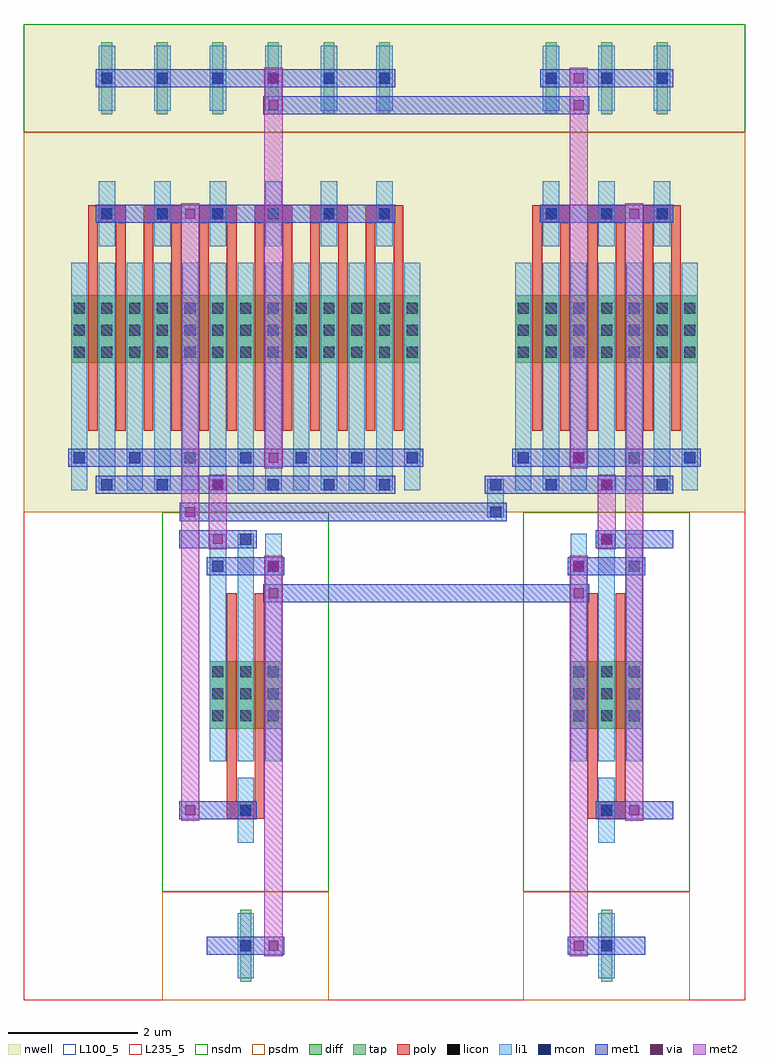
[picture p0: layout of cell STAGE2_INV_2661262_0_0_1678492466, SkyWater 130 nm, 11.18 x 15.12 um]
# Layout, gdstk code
from math import pi, radians
import gdstk
lib = gdstk.Library(unit=1e-6, precision=1e-09)
def R(c, l, rs):  # rectangles x0, y0, x1, y1
    for r in rs: c.add(gdstk.rectangle(r[:2], r[2:], *l))
def A(c, l, x, y, w, h, nx, ny, dx, dy):  # array of equal rectangles
    R(c, l, [(x+i*dx, y+j*dy, x+i*dx+w, y+j*dy+h) for i in range(nx) for j in range(ny)])
def P(c, l, *ps):  # polygons
    for p in ps: c.add(gdstk.Polygon(p, *l))
nwell = (64, 20)
diff = (65, 20)
tap = (65, 44)
poly = (66, 20)
licon = (66, 44)
li1 = (67, 20)
mcon = (67, 44)
met1 = (68, 20)
via = (68, 44)
met2 = (69, 20)
nsdm = (93, 44)
psdm = (94, 20)
L100_5 = (100, 5)
L235_5 = (235, 5)

nmos_s_54487678_x1_y1_16 = lib.new_cell('NMOS_S_54487678_X1_Y1_1678492463_1678492466')
R(nmos_s_54487678_x1_y1_16, diff, [(0.735,2.31,1.845,3.36)])
R(nmos_s_54487678_x1_y1_16, tap, [(1.205,6.16,1.375,7.28)])
R(nmos_s_54487678_x1_y1_16, poly, [(1,1.26,1.15,4.62), (1.43,1.26,1.58,4.62), (1,4.485,1.58,4.755)])
A(nmos_s_54487678_x1_y1_16, licon, 0.775, 2.39, 0.17, 0.17, 3, 3, 0.43, 0.34)
R(nmos_s_54487678_x1_y1_16, licon, [(1.205,4.535,1.375,4.705), (1.205,6.635,1.375,6.805)])
A(nmos_s_54487678_x1_y1_16, li1, 0.735, 0.335, 0.25, 3.53, 3, 1, 0.43, 0)
R(nmos_s_54487678_x1_y1_16, li1, [(1.165,4.115,1.415,5.125), (1.165,6.215,1.415,7.225)])
R(nmos_s_54487678_x1_y1_16, mcon, [(1.205,0.335,1.375,0.505), (0.775,0.755,0.945,0.925), (1.635,0.755,1.805,0.925), (1.205,4.535,1.375,4.705), (1.205,6.635,1.375,6.805)])
R(nmos_s_54487678_x1_y1_16, met1, [(0.26,0.28,1.46,0.56), (0.69,0.7,1.89,0.98), (0.26,4.48,1.46,4.76), (0.69,6.58,1.89,6.86)])
R(nmos_s_54487678_x1_y1_16, via, [(1.645,0.765,1.795,0.915), (1.645,6.645,1.795,6.795)])
R(nmos_s_54487678_x1_y1_16, met2, [(1.58,0.68,1.86,6.88)])
R(nmos_s_54487678_x1_y1_16, nsdm, [(0,0,2.58,5.88)])
R(nmos_s_54487678_x1_y1_16, psdm, [(0,5.88,2.58,7.56)])
R(nmos_s_54487678_x1_y1_16, L100_5, [(0,0,2.58,7.56)])

pmos_s_55262173_x3_y1_16 = lib.new_cell('PMOS_S_55262173_X3_Y1_1678492464_1678492466')
R(pmos_s_55262173_x3_y1_16, nwell, [(0,0,4.3,7.56)])
R(pmos_s_55262173_x3_y1_16, diff, [(0.735,2.31,3.565,3.36)])
A(pmos_s_55262173_x3_y1_16, tap, 1.205, 6.16, 0.17, 1.12, 3, 1, 0.86, 0)
A(pmos_s_55262173_x3_y1_16, poly, 1, 1.26, 0.15, 3.36, 6, 1, 0.43, 0)
A(pmos_s_55262173_x3_y1_16, poly, 1, 4.485, 0.58, 0.27, 3, 1, 0.86, 0)
A(pmos_s_55262173_x3_y1_16, licon, 0.775, 2.39, 0.17, 0.17, 3, 3, 0.43, 0.34)
A(pmos_s_55262173_x3_y1_16, licon, 1.635, 2.39, 0.17, 0.17, 3, 3, 0.43, 0.34)
A(pmos_s_55262173_x3_y1_16, licon, 2.495, 2.39, 0.17, 0.17, 3, 3, 0.43, 0.34)
A(pmos_s_55262173_x3_y1_16, licon, 1.205, 4.535, 0.17, 0.17, 3, 2, 0.86, 2.1)
A(pmos_s_55262173_x3_y1_16, li1, 0.735, 0.335, 0.25, 3.53, 7, 1, 0.43, 0)
A(pmos_s_55262173_x3_y1_16, li1, 1.165, 4.115, 0.25, 1.01, 3, 2, 0.86, 2.1)
A(pmos_s_55262173_x3_y1_16, mcon, 1.205, 0.335, 0.17, 0.17, 3, 2, 0.86, 4.2)
A(pmos_s_55262173_x3_y1_16, mcon, 0.775, 0.755, 0.17, 0.17, 4, 1, 0.86, 0)
A(pmos_s_55262173_x3_y1_16, mcon, 1.205, 6.635, 0.17, 0.17, 3, 1, 0.86, 0)
R(pmos_s_55262173_x3_y1_16, met1, [(1.12,0.28,3.18,0.56), (0.69,0.7,3.61,0.98), (1.12,4.48,3.18,4.76), (1.12,6.58,3.18,6.86)])
R(pmos_s_55262173_x3_y1_16, via, [(2.505,0.765,2.655,0.915), (2.505,6.645,2.655,6.795)])
R(pmos_s_55262173_x3_y1_16, met2, [(2.44,0.68,2.72,6.88)])
R(pmos_s_55262173_x3_y1_16, nsdm, [(0,5.88,4.3,7.56)])
R(pmos_s_55262173_x3_y1_16, psdm, [(0,0,4.3,5.88)])
R(pmos_s_55262173_x3_y1_16, L100_5, [(0,0,4.3,7.56)])

pmos_s_81354572_x6_y1_16 = lib.new_cell('PMOS_S_81354572_X6_Y1_1678492465_1678492466')
R(pmos_s_81354572_x6_y1_16, nwell, [(0,0,6.88,7.56)])
R(pmos_s_81354572_x6_y1_16, diff, [(0.735,2.31,6.145,3.36)])
A(pmos_s_81354572_x6_y1_16, tap, 1.205, 6.16, 0.17, 1.12, 6, 1, 0.86, 0)
A(pmos_s_81354572_x6_y1_16, poly, 1, 1.26, 0.15, 3.36, 12, 1, 0.43, 0)
A(pmos_s_81354572_x6_y1_16, poly, 1, 4.485, 0.58, 0.27, 6, 1, 0.86, 0)
A(pmos_s_81354572_x6_y1_16, licon, 0.775, 2.39, 0.17, 0.17, 3, 3, 0.43, 0.34)
A(pmos_s_81354572_x6_y1_16, licon, 1.635, 2.39, 0.17, 0.17, 3, 3, 0.43, 0.34)
A(pmos_s_81354572_x6_y1_16, licon, 2.495, 2.39, 0.17, 0.17, 3, 3, 0.43, 0.34)
A(pmos_s_81354572_x6_y1_16, licon, 3.355, 2.39, 0.17, 0.17, 3, 3, 0.43, 0.34)
A(pmos_s_81354572_x6_y1_16, licon, 4.215, 2.39, 0.17, 0.17, 3, 3, 0.43, 0.34)
A(pmos_s_81354572_x6_y1_16, licon, 5.075, 2.39, 0.17, 0.17, 3, 3, 0.43, 0.34)
A(pmos_s_81354572_x6_y1_16, licon, 1.205, 4.535, 0.17, 0.17, 6, 2, 0.86, 2.1)
A(pmos_s_81354572_x6_y1_16, li1, 0.735, 0.335, 0.25, 3.53, 13, 1, 0.43, 0)
A(pmos_s_81354572_x6_y1_16, li1, 1.165, 4.115, 0.25, 1.01, 6, 2, 0.86, 2.1)
A(pmos_s_81354572_x6_y1_16, mcon, 1.205, 0.335, 0.17, 0.17, 6, 2, 0.86, 4.2)
A(pmos_s_81354572_x6_y1_16, mcon, 0.775, 0.755, 0.17, 0.17, 7, 1, 0.86, 0)
A(pmos_s_81354572_x6_y1_16, mcon, 1.205, 6.635, 0.17, 0.17, 6, 1, 0.86, 0)
R(pmos_s_81354572_x6_y1_16, met1, [(1.12,0.28,5.76,0.56), (0.69,0.7,6.19,0.98), (1.12,4.48,5.76,4.76), (1.12,6.58,5.76,6.86)])
R(pmos_s_81354572_x6_y1_16, via, [(3.795,0.765,3.945,0.915), (3.795,6.645,3.945,6.795)])
R(pmos_s_81354572_x6_y1_16, met2, [(3.73,0.68,4.01,6.88)])
R(pmos_s_81354572_x6_y1_16, nsdm, [(0,5.88,6.88,7.56)])
R(pmos_s_81354572_x6_y1_16, psdm, [(0,0,6.88,5.88)])
R(pmos_s_81354572_x6_y1_16, L100_5, [(0,0,6.88,7.56)])

stage2_inv_2661262_0_0_1 = lib.new_cell('STAGE2_INV_2661262_0_0_1678492466')
R(stage2_inv_2661262_0_0_1, li1, [(7.185,7.475,7.435,7.645), (7.185,7.475,7.435,7.645), (7.185,7.475,7.435,7.645), (7.185,7.475,7.435,7.645), (7.185,7.56,7.435,7.98), (7.185,7.895,7.435,8.065), (7.185,7.895,7.435,8.065), (7.185,7.895,7.435,8.065), (7.185,7.895,7.435,8.065)])
R(stage2_inv_2661262_0_0_1, mcon, [(7.225,7.475,7.395,7.645), (7.225,7.475,7.395,7.645), (7.225,7.475,7.395,7.645), (7.225,7.475,7.395,7.645), (7.225,7.895,7.395,8.065), (7.225,7.895,7.395,8.065), (7.225,7.895,7.395,8.065), (7.225,7.895,7.395,8.065)])
R(stage2_inv_2661262_0_0_1, met1, [(2.42,2.8,2.74,3.08), (2.42,2.8,2.74,3.08), (2.42,2.8,2.74,3.08), (2.42,2.8,2.74,3.08), (2.42,2.8,2.74,3.08), (2.42,2.8,2.74,3.08), (9.3,2.8,9.62,3.08), (9.3,2.8,9.62,3.08), (3.71,6.16,4.03,6.44), (3.71,6.16,4.03,6.44), (3.87,6.16,8.6,6.44), (8.44,6.16,8.76,6.44), (8.44,6.16,8.76,6.44), (2.85,7,3.17,7.28), (2.85,7,3.17,7.28), (8.87,7,9.19,7.28), (8.87,7,9.19,7.28), (2.42,7.42,2.74,7.7), (2.42,7.42,2.74,7.7), (2.42,7.42,2.74,7.7), (2.42,7.42,2.74,7.7), (2.58,7.42,7.31,7.7), (7.14,7.42,7.48,7.7), (7.14,7.42,7.48,7.7), (7.14,7.42,7.48,7.7), (7.14,7.42,7.48,7.7), (2.85,7.84,3.17,8.12), (2.85,7.84,3.17,8.12), (7.14,7.84,7.48,8.12), (7.14,7.84,7.48,8.12), (7.14,7.84,7.48,8.12), (7.14,7.84,7.48,8.12), (7.31,7.84,8.17,8.12), (8.87,7.84,9.19,8.12), (8.87,7.84,9.19,8.12), (2.42,12.04,2.74,12.32), (2.42,12.04,2.74,12.32), (2.42,12.04,2.74,12.32), (2.42,12.04,2.74,12.32), (2.42,12.04,2.74,12.32), (2.42,12.04,2.74,12.32), (9.3,12.04,9.62,12.32), (9.3,12.04,9.62,12.32), (3.71,13.72,4.03,14), (3.71,13.72,4.03,14), (3.87,13.72,8.6,14), (8.44,13.72,8.76,14), (8.44,13.72,8.76,14)])
P(stage2_inv_2661262_0_0_1, met1, [(0,0),(0,0),(0,0),(0,0)],
  [(0,0),(0,0),(0,0),(0,0)],
  [(0,0),(0,0),(0,0),(0,0)],
  [(0,0),(0,0),(0,0),(0,0)],
  [(0,0),(0,0),(0,0),(0,0)],
  [(0,0),(0,0),(0,0),(0,0)],
  [(0,0),(0,0),(0,0),(0,0)],
  [(0,0),(0,0),(0,0),(0,0)])
R(stage2_inv_2661262_0_0_1, via, [(2.505,2.865,2.655,3.015), (2.505,2.865,2.655,3.015), (2.505,2.865,2.655,3.015), (2.505,2.865,2.655,3.015), (2.505,2.865,2.655,3.015), (2.505,2.865,2.655,3.015), (9.385,2.865,9.535,3.015), (9.385,2.865,9.535,3.015), (3.795,6.225,3.945,6.375), (3.795,6.225,3.945,6.375), (8.525,6.225,8.675,6.375), (8.525,6.225,8.675,6.375), (2.935,7.065,3.085,7.215), (2.935,7.065,3.085,7.215), (8.955,7.065,9.105,7.215), (8.955,7.065,9.105,7.215), (2.505,7.485,2.655,7.635), (2.505,7.485,2.655,7.635), (2.505,7.485,2.655,7.635), (2.505,7.485,2.655,7.635), (2.935,7.905,3.085,8.055), (2.935,7.905,3.085,8.055), (8.955,7.905,9.105,8.055), (8.955,7.905,9.105,8.055), (2.505,12.105,2.655,12.255), (2.505,12.105,2.655,12.255), (2.505,12.105,2.655,12.255), (2.505,12.105,2.655,12.255), (2.505,12.105,2.655,12.255), (2.505,12.105,2.655,12.255), (9.385,12.105,9.535,12.255), (9.385,12.105,9.535,12.255), (3.795,13.785,3.945,13.935), (3.795,13.785,3.945,13.935), (8.525,13.785,8.675,13.935), (8.525,13.785,8.675,13.935)])
R(stage2_inv_2661262_0_0_1, met2, [(2.44,2.78,2.72,3.1), (2.44,2.78,2.72,3.1), (2.44,2.78,2.72,3.1), (2.44,2.78,2.72,3.1), (2.44,2.78,2.72,3.1), (2.44,2.78,2.72,3.1), (9.32,2.78,9.6,3.1), (9.32,2.78,9.6,3.1), (2.44,2.94,2.72,12.18), (9.32,2.94,9.6,12.18), (3.73,6.14,4.01,6.46), (3.73,6.14,4.01,6.46), (8.46,6.14,8.74,6.46), (8.46,6.14,8.74,6.46), (2.87,6.98,3.15,7.3), (2.87,6.98,3.15,7.3), (8.89,6.98,9.17,7.3), (8.89,6.98,9.17,7.3), (2.87,7.14,3.15,7.98), (8.89,7.14,9.17,7.98), (2.44,7.4,2.72,7.72), (2.44,7.4,2.72,7.72), (2.44,7.4,2.72,7.72), (2.44,7.4,2.72,7.72), (2.87,7.82,3.15,8.14), (2.87,7.82,3.15,8.14), (8.89,7.82,9.17,8.14), (8.89,7.82,9.17,8.14), (2.44,12.02,2.72,12.34), (2.44,12.02,2.72,12.34), (2.44,12.02,2.72,12.34), (2.44,12.02,2.72,12.34), (2.44,12.02,2.72,12.34), (2.44,12.02,2.72,12.34), (9.32,12.02,9.6,12.34), (9.32,12.02,9.6,12.34), (3.73,13.7,4.01,14.02), (3.73,13.7,4.01,14.02), (8.46,13.7,8.74,14.02), (8.46,13.7,8.74,14.02)])
P(stage2_inv_2661262_0_0_1, met2, [(0,0),(0,0),(0,0),(0,0)],
  [(0,0),(0,0),(0,0),(0,0)],
  [(0,0),(0,0),(0,0),(0,0)],
  [(0,0),(0,0),(0,0),(0,0)])
R(stage2_inv_2661262_0_0_1, L235_5, [(0,0,11.18,15.12)])
stage2_inv_2661262_0_0_1.add(gdstk.Reference(nmos_s_54487678_x1_y1_16, (10.32,7.56), rotation=pi))
stage2_inv_2661262_0_0_1.add(gdstk.Reference(nmos_s_54487678_x1_y1_16, (2.15,7.56), x_reflection=True))
stage2_inv_2661262_0_0_1.add(gdstk.Reference(pmos_s_55262173_x3_y1_16, (11.18,7.56), rotation=pi, x_reflection=True))
stage2_inv_2661262_0_0_1.add(gdstk.Reference(pmos_s_81354572_x6_y1_16, (0,7.56)))

lib.write_gds('STAGE2_INV_2661262_0_0_1678492466.gds')
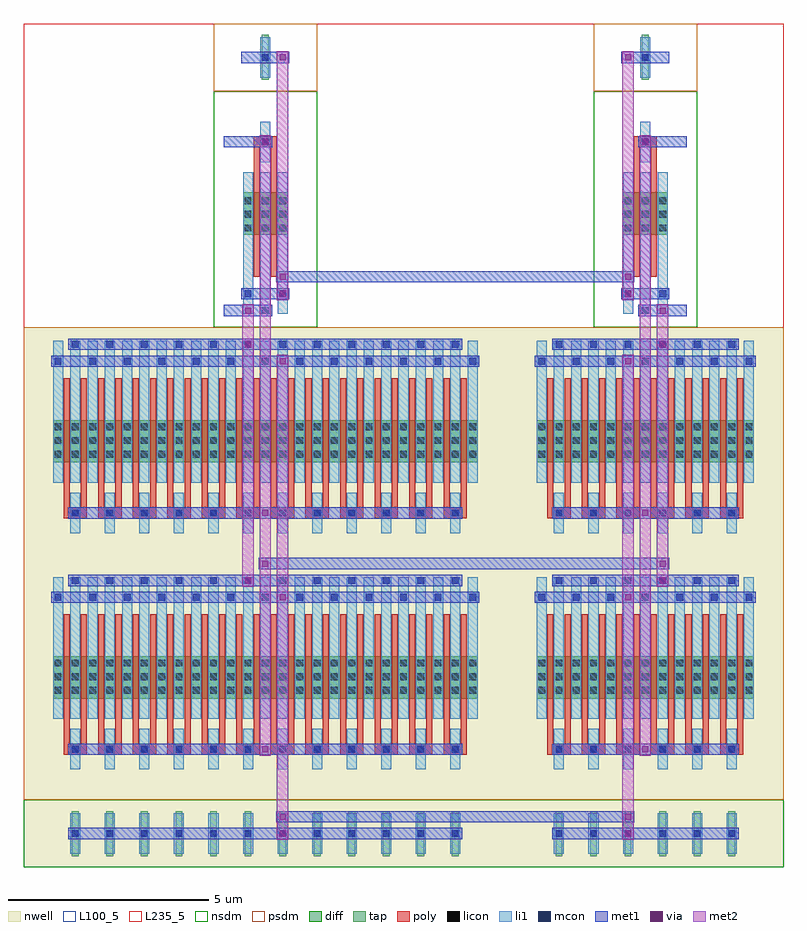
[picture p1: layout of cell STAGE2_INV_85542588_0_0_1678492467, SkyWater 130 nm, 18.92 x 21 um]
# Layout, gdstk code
from math import pi, radians
import gdstk
lib = gdstk.Library(unit=1e-6, precision=1e-09)
def R(c, l, rs):  # rectangles x0, y0, x1, y1
    for r in rs: c.add(gdstk.rectangle(r[:2], r[2:], *l))
def A(c, l, x, y, w, h, nx, ny, dx, dy):  # array of equal rectangles
    R(c, l, [(x+i*dx, y+j*dy, x+i*dx+w, y+j*dy+h) for i in range(nx) for j in range(ny)])
def P(c, l, *ps):  # polygons
    for p in ps: c.add(gdstk.Polygon(p, *l))
nwell = (64, 20)
diff = (65, 20)
tap = (65, 44)
poly = (66, 20)
licon = (66, 44)
li1 = (67, 20)
mcon = (67, 44)
met1 = (68, 20)
via = (68, 44)
met2 = (69, 20)
nsdm = (93, 44)
psdm = (94, 20)
L100_5 = (100, 5)
L235_5 = (235, 5)

nmos_s_54487678_x1_y1_16 = lib.new_cell('NMOS_S_54487678_X1_Y1_1678492463_1678492467')
R(nmos_s_54487678_x1_y1_16, diff, [(0.735,2.31,1.845,3.36)])
R(nmos_s_54487678_x1_y1_16, tap, [(1.205,6.16,1.375,7.28)])
R(nmos_s_54487678_x1_y1_16, poly, [(1,1.26,1.15,4.62), (1.43,1.26,1.58,4.62), (1,4.485,1.58,4.755)])
A(nmos_s_54487678_x1_y1_16, licon, 0.775, 2.39, 0.17, 0.17, 3, 3, 0.43, 0.34)
R(nmos_s_54487678_x1_y1_16, licon, [(1.205,4.535,1.375,4.705), (1.205,6.635,1.375,6.805)])
A(nmos_s_54487678_x1_y1_16, li1, 0.735, 0.335, 0.25, 3.53, 3, 1, 0.43, 0)
R(nmos_s_54487678_x1_y1_16, li1, [(1.165,4.115,1.415,5.125), (1.165,6.215,1.415,7.225)])
R(nmos_s_54487678_x1_y1_16, mcon, [(1.205,0.335,1.375,0.505), (0.775,0.755,0.945,0.925), (1.635,0.755,1.805,0.925), (1.205,4.535,1.375,4.705), (1.205,6.635,1.375,6.805)])
R(nmos_s_54487678_x1_y1_16, met1, [(0.26,0.28,1.46,0.56), (0.69,0.7,1.89,0.98), (0.26,4.48,1.46,4.76), (0.69,6.58,1.89,6.86)])
R(nmos_s_54487678_x1_y1_16, via, [(1.645,0.765,1.795,0.915), (1.645,6.645,1.795,6.795)])
R(nmos_s_54487678_x1_y1_16, met2, [(1.58,0.68,1.86,6.88)])
R(nmos_s_54487678_x1_y1_16, nsdm, [(0,0,2.58,5.88)])
R(nmos_s_54487678_x1_y1_16, psdm, [(0,5.88,2.58,7.56)])
R(nmos_s_54487678_x1_y1_16, L100_5, [(0,0,2.58,7.56)])

pmos_s_67711244_x6_y2_16 = lib.new_cell('PMOS_S_67711244_X6_Y2_1678492465_1678492467')
R(pmos_s_67711244_x6_y2_16, nwell, [(0,0,6.88,13.44)])
R(pmos_s_67711244_x6_y2_16, diff, [(0.735,2.31,6.145,3.36), (0.735,8.19,6.145,9.24)])
A(pmos_s_67711244_x6_y2_16, tap, 1.205, 12.04, 0.17, 1.12, 6, 1, 0.86, 0)
A(pmos_s_67711244_x6_y2_16, poly, 1, 1.26, 0.15, 3.36, 12, 2, 0.43, 5.88)
A(pmos_s_67711244_x6_y2_16, poly, 1, 4.485, 0.58, 0.27, 6, 2, 0.86, 5.88)
A(pmos_s_67711244_x6_y2_16, licon, 0.775, 2.39, 0.17, 0.17, 3, 3, 0.43, 0.34)
A(pmos_s_67711244_x6_y2_16, licon, 1.635, 2.39, 0.17, 0.17, 3, 3, 0.43, 0.34)
A(pmos_s_67711244_x6_y2_16, licon, 2.495, 2.39, 0.17, 0.17, 3, 3, 0.43, 0.34)
A(pmos_s_67711244_x6_y2_16, licon, 3.355, 2.39, 0.17, 0.17, 3, 3, 0.43, 0.34)
A(pmos_s_67711244_x6_y2_16, licon, 4.215, 2.39, 0.17, 0.17, 3, 3, 0.43, 0.34)
A(pmos_s_67711244_x6_y2_16, licon, 5.075, 2.39, 0.17, 0.17, 3, 3, 0.43, 0.34)
A(pmos_s_67711244_x6_y2_16, licon, 1.205, 4.535, 0.17, 0.17, 6, 2, 0.86, 5.88)
A(pmos_s_67711244_x6_y2_16, licon, 0.775, 8.27, 0.17, 0.17, 3, 3, 0.43, 0.34)
A(pmos_s_67711244_x6_y2_16, licon, 1.635, 8.27, 0.17, 0.17, 3, 3, 0.43, 0.34)
A(pmos_s_67711244_x6_y2_16, licon, 2.495, 8.27, 0.17, 0.17, 3, 3, 0.43, 0.34)
A(pmos_s_67711244_x6_y2_16, licon, 3.355, 8.27, 0.17, 0.17, 3, 3, 0.43, 0.34)
A(pmos_s_67711244_x6_y2_16, licon, 4.215, 8.27, 0.17, 0.17, 3, 3, 0.43, 0.34)
A(pmos_s_67711244_x6_y2_16, licon, 5.075, 8.27, 0.17, 0.17, 3, 3, 0.43, 0.34)
R(pmos_s_67711244_x6_y2_16, licon, [(1.205,12.515,1.375,12.685), (1.205,12.515,1.375,12.685), (2.065,12.515,2.235,12.685), (2.065,12.515,2.235,12.685), (2.925,12.515,3.095,12.685), (2.925,12.515,3.095,12.685), (3.785,12.515,3.955,12.685), (3.785,12.515,3.955,12.685), (4.645,12.515,4.815,12.685), (4.645,12.515,4.815,12.685), (5.505,12.515,5.675,12.685), (5.505,12.515,5.675,12.685)])
A(pmos_s_67711244_x6_y2_16, li1, 0.735, 0.335, 0.25, 3.53, 13, 2, 0.43, 5.88)
A(pmos_s_67711244_x6_y2_16, li1, 1.165, 4.115, 0.25, 1.01, 6, 2, 0.86, 5.88)
A(pmos_s_67711244_x6_y2_16, li1, 1.165, 12.095, 0.25, 1.01, 6, 1, 0.86, 0)
A(pmos_s_67711244_x6_y2_16, mcon, 1.205, 0.335, 0.17, 0.17, 6, 2, 0.86, 4.2)
A(pmos_s_67711244_x6_y2_16, mcon, 0.775, 0.755, 0.17, 0.17, 7, 2, 0.86, 5.88)
A(pmos_s_67711244_x6_y2_16, mcon, 1.205, 6.215, 0.17, 0.17, 6, 2, 0.86, 4.2)
A(pmos_s_67711244_x6_y2_16, mcon, 1.205, 12.515, 0.17, 0.17, 6, 1, 0.86, 0)
R(pmos_s_67711244_x6_y2_16, met1, [(1.12,0.28,5.76,0.56), (0.69,0.7,6.19,0.98), (1.12,4.48,5.76,4.76), (1.12,6.16,5.76,6.44), (0.69,6.58,6.19,6.86), (1.12,10.36,5.76,10.64), (1.12,12.46,5.76,12.74)])
A(pmos_s_67711244_x6_y2_16, via, 3.795, 0.765, 0.15, 0.15, 1, 3, 0, 5.88)
R(pmos_s_67711244_x6_y2_16, via, [(2.935,0.345,3.085,0.495), (3.365,4.545,3.515,4.695), (2.935,6.225,3.085,6.375), (3.365,10.425,3.515,10.575)])
R(pmos_s_67711244_x6_y2_16, met2, [(2.87,0.26,3.15,6.46), (3.73,0.68,4.01,12.76), (3.3,4.46,3.58,10.66)])
R(pmos_s_67711244_x6_y2_16, nsdm, [(0,11.76,6.88,13.44)])
R(pmos_s_67711244_x6_y2_16, psdm, [(0,0,6.88,11.76)])
R(pmos_s_67711244_x6_y2_16, L100_5, [(0,0,6.88,13.44)])

pmos_s_2470631_x12_y2_16 = lib.new_cell('PMOS_S_2470631_X12_Y2_1678492464_1678492467')
R(pmos_s_2470631_x12_y2_16, nwell, [(0,0,12.04,13.44)])
R(pmos_s_2470631_x12_y2_16, diff, [(0.735,2.31,11.305,3.36), (0.735,8.19,11.305,9.24)])
A(pmos_s_2470631_x12_y2_16, tap, 1.205, 12.04, 0.17, 1.12, 12, 1, 0.86, 0)
A(pmos_s_2470631_x12_y2_16, poly, 1, 1.26, 0.15, 3.36, 24, 2, 0.43, 5.88)
A(pmos_s_2470631_x12_y2_16, poly, 1, 4.485, 0.58, 0.27, 12, 2, 0.86, 5.88)
A(pmos_s_2470631_x12_y2_16, licon, 0.775, 2.39, 0.17, 0.17, 3, 3, 0.43, 0.34)
A(pmos_s_2470631_x12_y2_16, licon, 1.635, 2.39, 0.17, 0.17, 3, 3, 0.43, 0.34)
A(pmos_s_2470631_x12_y2_16, licon, 2.495, 2.39, 0.17, 0.17, 3, 3, 0.43, 0.34)
A(pmos_s_2470631_x12_y2_16, licon, 3.355, 2.39, 0.17, 0.17, 3, 3, 0.43, 0.34)
A(pmos_s_2470631_x12_y2_16, licon, 4.215, 2.39, 0.17, 0.17, 3, 3, 0.43, 0.34)
A(pmos_s_2470631_x12_y2_16, licon, 5.075, 2.39, 0.17, 0.17, 3, 3, 0.43, 0.34)
A(pmos_s_2470631_x12_y2_16, licon, 5.935, 2.39, 0.17, 0.17, 3, 3, 0.43, 0.34)
A(pmos_s_2470631_x12_y2_16, licon, 6.795, 2.39, 0.17, 0.17, 3, 3, 0.43, 0.34)
A(pmos_s_2470631_x12_y2_16, licon, 7.655, 2.39, 0.17, 0.17, 3, 3, 0.43, 0.34)
A(pmos_s_2470631_x12_y2_16, licon, 8.515, 2.39, 0.17, 0.17, 3, 3, 0.43, 0.34)
A(pmos_s_2470631_x12_y2_16, licon, 9.375, 2.39, 0.17, 0.17, 3, 3, 0.43, 0.34)
A(pmos_s_2470631_x12_y2_16, licon, 10.235, 2.39, 0.17, 0.17, 3, 3, 0.43, 0.34)
A(pmos_s_2470631_x12_y2_16, licon, 1.205, 4.535, 0.17, 0.17, 12, 2, 0.86, 5.88)
A(pmos_s_2470631_x12_y2_16, licon, 0.775, 8.27, 0.17, 0.17, 3, 3, 0.43, 0.34)
A(pmos_s_2470631_x12_y2_16, licon, 1.635, 8.27, 0.17, 0.17, 3, 3, 0.43, 0.34)
A(pmos_s_2470631_x12_y2_16, licon, 2.495, 8.27, 0.17, 0.17, 3, 3, 0.43, 0.34)
A(pmos_s_2470631_x12_y2_16, licon, 3.355, 8.27, 0.17, 0.17, 3, 3, 0.43, 0.34)
A(pmos_s_2470631_x12_y2_16, licon, 4.215, 8.27, 0.17, 0.17, 3, 3, 0.43, 0.34)
A(pmos_s_2470631_x12_y2_16, licon, 5.075, 8.27, 0.17, 0.17, 3, 3, 0.43, 0.34)
A(pmos_s_2470631_x12_y2_16, licon, 5.935, 8.27, 0.17, 0.17, 3, 3, 0.43, 0.34)
A(pmos_s_2470631_x12_y2_16, licon, 6.795, 8.27, 0.17, 0.17, 3, 3, 0.43, 0.34)
A(pmos_s_2470631_x12_y2_16, licon, 7.655, 8.27, 0.17, 0.17, 3, 3, 0.43, 0.34)
A(pmos_s_2470631_x12_y2_16, licon, 8.515, 8.27, 0.17, 0.17, 3, 3, 0.43, 0.34)
A(pmos_s_2470631_x12_y2_16, licon, 9.375, 8.27, 0.17, 0.17, 3, 3, 0.43, 0.34)
A(pmos_s_2470631_x12_y2_16, licon, 10.235, 8.27, 0.17, 0.17, 3, 3, 0.43, 0.34)
R(pmos_s_2470631_x12_y2_16, licon, [(1.205,12.515,1.375,12.685), (1.205,12.515,1.375,12.685), (2.065,12.515,2.235,12.685), (2.065,12.515,2.235,12.685), (2.925,12.515,3.095,12.685), (2.925,12.515,3.095,12.685), (3.785,12.515,3.955,12.685), (3.785,12.515,3.955,12.685), (4.645,12.515,4.815,12.685), (4.645,12.515,4.815,12.685), (5.505,12.515,5.675,12.685), (5.505,12.515,5.675,12.685), (6.365,12.515,6.535,12.685), (6.365,12.515,6.535,12.685), (7.225,12.515,7.395,12.685), (7.225,12.515,7.395,12.685), (8.085,12.515,8.255,12.685), (8.085,12.515,8.255,12.685), (8.945,12.515,9.115,12.685), (8.945,12.515,9.115,12.685), (9.805,12.515,9.975,12.685), (9.805,12.515,9.975,12.685), (10.665,12.515,10.835,12.685), (10.665,12.515,10.835,12.685)])
A(pmos_s_2470631_x12_y2_16, li1, 0.735, 0.335, 0.25, 3.53, 25, 2, 0.43, 5.88)
A(pmos_s_2470631_x12_y2_16, li1, 1.165, 4.115, 0.25, 1.01, 12, 2, 0.86, 5.88)
A(pmos_s_2470631_x12_y2_16, li1, 1.165, 12.095, 0.25, 1.01, 12, 1, 0.86, 0)
A(pmos_s_2470631_x12_y2_16, mcon, 1.205, 0.335, 0.17, 0.17, 12, 2, 0.86, 4.2)
A(pmos_s_2470631_x12_y2_16, mcon, 0.775, 0.755, 0.17, 0.17, 13, 2, 0.86, 5.88)
A(pmos_s_2470631_x12_y2_16, mcon, 1.205, 6.215, 0.17, 0.17, 12, 2, 0.86, 4.2)
A(pmos_s_2470631_x12_y2_16, mcon, 1.205, 12.515, 0.17, 0.17, 12, 1, 0.86, 0)
R(pmos_s_2470631_x12_y2_16, met1, [(1.12,0.28,10.92,0.56), (0.69,0.7,11.35,0.98), (1.12,4.48,10.92,4.76), (1.12,6.16,10.92,6.44), (0.69,6.58,11.35,6.86), (1.12,10.36,10.92,10.64), (1.12,12.46,10.92,12.74)])
A(pmos_s_2470631_x12_y2_16, via, 6.375, 0.765, 0.15, 0.15, 1, 3, 0, 5.88)
R(pmos_s_2470631_x12_y2_16, via, [(5.515,0.345,5.665,0.495), (5.945,4.545,6.095,4.695), (5.515,6.225,5.665,6.375), (5.945,10.425,6.095,10.575)])
R(pmos_s_2470631_x12_y2_16, met2, [(5.45,0.26,5.73,6.46), (6.31,0.68,6.59,12.76), (5.88,4.46,6.16,10.66)])
R(pmos_s_2470631_x12_y2_16, nsdm, [(0,11.76,12.04,13.44)])
R(pmos_s_2470631_x12_y2_16, psdm, [(0,0,12.04,11.76)])
R(pmos_s_2470631_x12_y2_16, L100_5, [(0,0,12.04,13.44)])

stage2_inv_85542588_0_0_ = lib.new_cell('STAGE2_INV_85542588_0_0_1678492467')
R(stage2_inv_85542588_0_0_, met1, [(6.29,1.12,6.61,1.4), (6.29,1.12,6.61,1.4), (6.45,1.12,15.05,1.4), (14.89,1.12,15.21,1.4), (14.89,1.12,15.21,1.4), (5.86,7.42,6.18,7.7), (5.86,7.42,6.18,7.7), (5.86,7.42,6.18,7.7), (5.86,7.42,6.18,7.7), (6.02,7.42,15.91,7.7), (15.75,7.42,16.07,7.7), (15.75,7.42,16.07,7.7), (15.75,7.42,16.07,7.7), (15.75,7.42,16.07,7.7), (5.43,13.72,5.75,14), (5.43,13.72,5.75,14), (15.75,13.72,16.07,14), (15.75,13.72,16.07,14), (6.29,14.56,6.61,14.84), (6.29,14.56,6.61,14.84), (6.45,14.56,15.05,14.84), (14.89,14.56,15.21,14.84), (14.89,14.56,15.21,14.84), (5.86,17.92,6.18,18.2), (5.86,17.92,6.18,18.2), (5.86,17.92,6.18,18.2), (5.86,17.92,6.18,18.2), (5.86,17.92,6.18,18.2), (5.86,17.92,6.18,18.2), (15.32,17.92,15.64,18.2), (15.32,17.92,15.64,18.2)])
P(stage2_inv_85542588_0_0_, met1, [(0,0),(0,0),(0,0),(0,0)],
  [(0,0),(0,0),(0,0),(0,0)],
  [(0,0),(0,0),(0,0),(0,0)],
  [(0,0),(0,0),(0,0),(0,0)])
R(stage2_inv_85542588_0_0_, via, [(6.375,1.185,6.525,1.335), (6.375,1.185,6.525,1.335), (14.975,1.185,15.125,1.335), (14.975,1.185,15.125,1.335), (5.945,7.485,6.095,7.635), (5.945,7.485,6.095,7.635), (5.945,7.485,6.095,7.635), (5.945,7.485,6.095,7.635), (15.835,7.485,15.985,7.635), (15.835,7.485,15.985,7.635), (15.835,7.485,15.985,7.635), (15.835,7.485,15.985,7.635), (5.515,13.785,5.665,13.935), (5.515,13.785,5.665,13.935), (15.835,13.785,15.985,13.935), (15.835,13.785,15.985,13.935), (6.375,14.625,6.525,14.775), (6.375,14.625,6.525,14.775), (14.975,14.625,15.125,14.775), (14.975,14.625,15.125,14.775), (5.945,17.985,6.095,18.135), (5.945,17.985,6.095,18.135), (5.945,17.985,6.095,18.135), (5.945,17.985,6.095,18.135), (5.945,17.985,6.095,18.135), (5.945,17.985,6.095,18.135), (15.405,17.985,15.555,18.135), (15.405,17.985,15.555,18.135)])
R(stage2_inv_85542588_0_0_, met2, [(6.31,1.1,6.59,1.42), (6.31,1.1,6.59,1.42), (14.91,1.1,15.19,1.42), (14.91,1.1,15.19,1.42), (5.88,7.4,6.16,7.72), (5.88,7.4,6.16,7.72), (5.88,7.4,6.16,7.72), (5.88,7.4,6.16,7.72), (15.77,7.4,16.05,7.72), (15.77,7.4,16.05,7.72), (15.77,7.4,16.05,7.72), (15.77,7.4,16.05,7.72), (5.88,8.82,6.16,18.06), (15.34,8.82,15.62,18.06), (5.45,13.02,5.73,13.86), (15.77,13.02,16.05,13.86), (5.45,13.7,5.73,14.02), (5.45,13.7,5.73,14.02), (15.77,13.7,16.05,14.02), (15.77,13.7,16.05,14.02), (6.31,14.54,6.59,14.86), (6.31,14.54,6.59,14.86), (14.91,14.54,15.19,14.86), (14.91,14.54,15.19,14.86), (5.88,17.9,6.16,18.22), (5.88,17.9,6.16,18.22), (5.88,17.9,6.16,18.22), (5.88,17.9,6.16,18.22), (5.88,17.9,6.16,18.22), (5.88,17.9,6.16,18.22), (15.34,17.9,15.62,18.22), (15.34,17.9,15.62,18.22)])
P(stage2_inv_85542588_0_0_, met2, [(0,0),(0,0),(0,0),(0,0)],
  [(0,0),(0,0),(0,0),(0,0)],
  [(0,0),(0,0),(0,0),(0,0)],
  [(0,0),(0,0),(0,0),(0,0)],
  [(0,0),(0,0),(0,0),(0,0)],
  [(0,0),(0,0),(0,0),(0,0)],
  [(0,0),(0,0),(0,0),(0,0)],
  [(0,0),(0,0),(0,0),(0,0)])
R(stage2_inv_85542588_0_0_, L235_5, [(0,0,18.92,21)])
stage2_inv_85542588_0_0_.add(gdstk.Reference(nmos_s_54487678_x1_y1_16, (16.77,13.44), rotation=pi, x_reflection=True))
stage2_inv_85542588_0_0_.add(gdstk.Reference(nmos_s_54487678_x1_y1_16, (4.73,13.44)))
stage2_inv_85542588_0_0_.add(gdstk.Reference(pmos_s_67711244_x6_y2_16, (18.92,13.44), rotation=pi))
stage2_inv_85542588_0_0_.add(gdstk.Reference(pmos_s_2470631_x12_y2_16, (0,13.44), x_reflection=True))

lib.write_gds('STAGE2_INV_85542588_0_0_1678492467.gds')
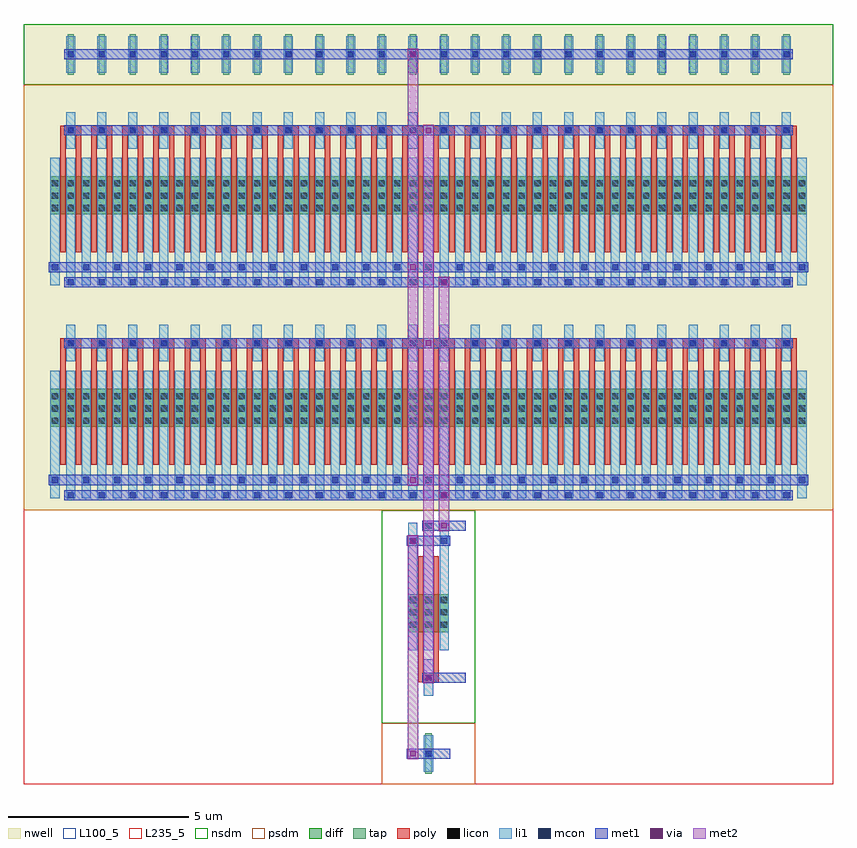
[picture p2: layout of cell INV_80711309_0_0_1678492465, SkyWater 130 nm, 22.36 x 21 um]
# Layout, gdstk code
from math import pi, radians
import gdstk
lib = gdstk.Library(unit=1e-6, precision=1e-09)
def R(c, l, rs):  # rectangles x0, y0, x1, y1
    for r in rs: c.add(gdstk.rectangle(r[:2], r[2:], *l))
def A(c, l, x, y, w, h, nx, ny, dx, dy):  # array of equal rectangles
    R(c, l, [(x+i*dx, y+j*dy, x+i*dx+w, y+j*dy+h) for i in range(nx) for j in range(ny)])
def P(c, l, *ps):  # polygons
    for p in ps: c.add(gdstk.Polygon(p, *l))
nwell = (64, 20)
diff = (65, 20)
tap = (65, 44)
poly = (66, 20)
licon = (66, 44)
li1 = (67, 20)
mcon = (67, 44)
met1 = (68, 20)
via = (68, 44)
met2 = (69, 20)
nsdm = (93, 44)
psdm = (94, 20)
L100_5 = (100, 5)
L235_5 = (235, 5)

nmos_s_54487678_x1_y1_16 = lib.new_cell('NMOS_S_54487678_X1_Y1_1678492463_1678492465')
R(nmos_s_54487678_x1_y1_16, diff, [(0.735,2.31,1.845,3.36)])
R(nmos_s_54487678_x1_y1_16, tap, [(1.205,6.16,1.375,7.28)])
R(nmos_s_54487678_x1_y1_16, poly, [(1,1.26,1.15,4.62), (1.43,1.26,1.58,4.62), (1,4.485,1.58,4.755)])
A(nmos_s_54487678_x1_y1_16, licon, 0.775, 2.39, 0.17, 0.17, 3, 3, 0.43, 0.34)
R(nmos_s_54487678_x1_y1_16, licon, [(1.205,4.535,1.375,4.705), (1.205,6.635,1.375,6.805)])
A(nmos_s_54487678_x1_y1_16, li1, 0.735, 0.335, 0.25, 3.53, 3, 1, 0.43, 0)
R(nmos_s_54487678_x1_y1_16, li1, [(1.165,4.115,1.415,5.125), (1.165,6.215,1.415,7.225)])
R(nmos_s_54487678_x1_y1_16, mcon, [(1.205,0.335,1.375,0.505), (0.775,0.755,0.945,0.925), (1.635,0.755,1.805,0.925), (1.205,4.535,1.375,4.705), (1.205,6.635,1.375,6.805)])
R(nmos_s_54487678_x1_y1_16, met1, [(0.26,0.28,1.46,0.56), (0.69,0.7,1.89,0.98), (0.26,4.48,1.46,4.76), (0.69,6.58,1.89,6.86)])
R(nmos_s_54487678_x1_y1_16, via, [(1.645,0.765,1.795,0.915), (1.645,6.645,1.795,6.795)])
R(nmos_s_54487678_x1_y1_16, met2, [(1.58,0.68,1.86,6.88)])
R(nmos_s_54487678_x1_y1_16, nsdm, [(0,0,2.58,5.88)])
R(nmos_s_54487678_x1_y1_16, psdm, [(0,5.88,2.58,7.56)])
R(nmos_s_54487678_x1_y1_16, L100_5, [(0,0,2.58,7.56)])

pmos_s_71888108_x24_y2_1 = lib.new_cell('PMOS_S_71888108_X24_Y2_1678492464_1678492465')
R(pmos_s_71888108_x24_y2_1, nwell, [(0,0,22.36,13.44)])
R(pmos_s_71888108_x24_y2_1, diff, [(0.735,2.31,21.625,3.36), (0.735,8.19,21.625,9.24)])
A(pmos_s_71888108_x24_y2_1, tap, 1.205, 12.04, 0.17, 1.12, 24, 1, 0.86, 0)
A(pmos_s_71888108_x24_y2_1, poly, 1, 1.26, 0.15, 3.36, 48, 2, 0.43, 5.88)
A(pmos_s_71888108_x24_y2_1, poly, 1, 4.485, 0.58, 0.27, 24, 2, 0.86, 5.88)
A(pmos_s_71888108_x24_y2_1, licon, 0.775, 2.39, 0.17, 0.17, 3, 3, 0.43, 0.34)
A(pmos_s_71888108_x24_y2_1, licon, 1.635, 2.39, 0.17, 0.17, 3, 3, 0.43, 0.34)
A(pmos_s_71888108_x24_y2_1, licon, 2.495, 2.39, 0.17, 0.17, 3, 3, 0.43, 0.34)
A(pmos_s_71888108_x24_y2_1, licon, 3.355, 2.39, 0.17, 0.17, 3, 3, 0.43, 0.34)
A(pmos_s_71888108_x24_y2_1, licon, 4.215, 2.39, 0.17, 0.17, 3, 3, 0.43, 0.34)
A(pmos_s_71888108_x24_y2_1, licon, 5.075, 2.39, 0.17, 0.17, 3, 3, 0.43, 0.34)
A(pmos_s_71888108_x24_y2_1, licon, 5.935, 2.39, 0.17, 0.17, 3, 3, 0.43, 0.34)
A(pmos_s_71888108_x24_y2_1, licon, 6.795, 2.39, 0.17, 0.17, 3, 3, 0.43, 0.34)
A(pmos_s_71888108_x24_y2_1, licon, 7.655, 2.39, 0.17, 0.17, 3, 3, 0.43, 0.34)
A(pmos_s_71888108_x24_y2_1, licon, 8.515, 2.39, 0.17, 0.17, 3, 3, 0.43, 0.34)
A(pmos_s_71888108_x24_y2_1, licon, 9.375, 2.39, 0.17, 0.17, 3, 3, 0.43, 0.34)
A(pmos_s_71888108_x24_y2_1, licon, 10.235, 2.39, 0.17, 0.17, 3, 3, 0.43, 0.34)
A(pmos_s_71888108_x24_y2_1, licon, 11.095, 2.39, 0.17, 0.17, 3, 3, 0.43, 0.34)
A(pmos_s_71888108_x24_y2_1, licon, 11.955, 2.39, 0.17, 0.17, 3, 3, 0.43, 0.34)
A(pmos_s_71888108_x24_y2_1, licon, 12.815, 2.39, 0.17, 0.17, 3, 3, 0.43, 0.34)
A(pmos_s_71888108_x24_y2_1, licon, 13.675, 2.39, 0.17, 0.17, 3, 3, 0.43, 0.34)
A(pmos_s_71888108_x24_y2_1, licon, 14.535, 2.39, 0.17, 0.17, 3, 3, 0.43, 0.34)
A(pmos_s_71888108_x24_y2_1, licon, 15.395, 2.39, 0.17, 0.17, 3, 3, 0.43, 0.34)
A(pmos_s_71888108_x24_y2_1, licon, 16.255, 2.39, 0.17, 0.17, 3, 3, 0.43, 0.34)
A(pmos_s_71888108_x24_y2_1, licon, 17.115, 2.39, 0.17, 0.17, 3, 3, 0.43, 0.34)
A(pmos_s_71888108_x24_y2_1, licon, 17.975, 2.39, 0.17, 0.17, 3, 3, 0.43, 0.34)
A(pmos_s_71888108_x24_y2_1, licon, 18.835, 2.39, 0.17, 0.17, 3, 3, 0.43, 0.34)
A(pmos_s_71888108_x24_y2_1, licon, 19.695, 2.39, 0.17, 0.17, 3, 3, 0.43, 0.34)
A(pmos_s_71888108_x24_y2_1, licon, 20.555, 2.39, 0.17, 0.17, 3, 3, 0.43, 0.34)
A(pmos_s_71888108_x24_y2_1, licon, 1.205, 4.535, 0.17, 0.17, 24, 2, 0.86, 5.88)
A(pmos_s_71888108_x24_y2_1, licon, 0.775, 8.27, 0.17, 0.17, 3, 3, 0.43, 0.34)
A(pmos_s_71888108_x24_y2_1, licon, 1.635, 8.27, 0.17, 0.17, 3, 3, 0.43, 0.34)
A(pmos_s_71888108_x24_y2_1, licon, 2.495, 8.27, 0.17, 0.17, 3, 3, 0.43, 0.34)
A(pmos_s_71888108_x24_y2_1, licon, 3.355, 8.27, 0.17, 0.17, 3, 3, 0.43, 0.34)
A(pmos_s_71888108_x24_y2_1, licon, 4.215, 8.27, 0.17, 0.17, 3, 3, 0.43, 0.34)
A(pmos_s_71888108_x24_y2_1, licon, 5.075, 8.27, 0.17, 0.17, 3, 3, 0.43, 0.34)
A(pmos_s_71888108_x24_y2_1, licon, 5.935, 8.27, 0.17, 0.17, 3, 3, 0.43, 0.34)
A(pmos_s_71888108_x24_y2_1, licon, 6.795, 8.27, 0.17, 0.17, 3, 3, 0.43, 0.34)
A(pmos_s_71888108_x24_y2_1, licon, 7.655, 8.27, 0.17, 0.17, 3, 3, 0.43, 0.34)
A(pmos_s_71888108_x24_y2_1, licon, 8.515, 8.27, 0.17, 0.17, 3, 3, 0.43, 0.34)
A(pmos_s_71888108_x24_y2_1, licon, 9.375, 8.27, 0.17, 0.17, 3, 3, 0.43, 0.34)
A(pmos_s_71888108_x24_y2_1, licon, 10.235, 8.27, 0.17, 0.17, 3, 3, 0.43, 0.34)
A(pmos_s_71888108_x24_y2_1, licon, 11.095, 8.27, 0.17, 0.17, 3, 3, 0.43, 0.34)
A(pmos_s_71888108_x24_y2_1, licon, 11.955, 8.27, 0.17, 0.17, 3, 3, 0.43, 0.34)
A(pmos_s_71888108_x24_y2_1, licon, 12.815, 8.27, 0.17, 0.17, 3, 3, 0.43, 0.34)
A(pmos_s_71888108_x24_y2_1, licon, 13.675, 8.27, 0.17, 0.17, 3, 3, 0.43, 0.34)
A(pmos_s_71888108_x24_y2_1, licon, 14.535, 8.27, 0.17, 0.17, 3, 3, 0.43, 0.34)
A(pmos_s_71888108_x24_y2_1, licon, 15.395, 8.27, 0.17, 0.17, 3, 3, 0.43, 0.34)
A(pmos_s_71888108_x24_y2_1, licon, 16.255, 8.27, 0.17, 0.17, 3, 3, 0.43, 0.34)
A(pmos_s_71888108_x24_y2_1, licon, 17.115, 8.27, 0.17, 0.17, 3, 3, 0.43, 0.34)
A(pmos_s_71888108_x24_y2_1, licon, 17.975, 8.27, 0.17, 0.17, 3, 3, 0.43, 0.34)
A(pmos_s_71888108_x24_y2_1, licon, 18.835, 8.27, 0.17, 0.17, 3, 3, 0.43, 0.34)
A(pmos_s_71888108_x24_y2_1, licon, 19.695, 8.27, 0.17, 0.17, 3, 3, 0.43, 0.34)
A(pmos_s_71888108_x24_y2_1, licon, 20.555, 8.27, 0.17, 0.17, 3, 3, 0.43, 0.34)
R(pmos_s_71888108_x24_y2_1, licon, [(1.205,12.515,1.375,12.685), (1.205,12.515,1.375,12.685), (2.065,12.515,2.235,12.685), (2.065,12.515,2.235,12.685), (2.925,12.515,3.095,12.685), (2.925,12.515,3.095,12.685), (3.785,12.515,3.955,12.685), (3.785,12.515,3.955,12.685), (4.645,12.515,4.815,12.685), (4.645,12.515,4.815,12.685), (5.505,12.515,5.675,12.685), (5.505,12.515,5.675,12.685), (6.365,12.515,6.535,12.685), (6.365,12.515,6.535,12.685), (7.225,12.515,7.395,12.685), (7.225,12.515,7.395,12.685), (8.085,12.515,8.255,12.685), (8.085,12.515,8.255,12.685), (8.945,12.515,9.115,12.685), (8.945,12.515,9.115,12.685), (9.805,12.515,9.975,12.685), (9.805,12.515,9.975,12.685), (10.665,12.515,10.835,12.685), (10.665,12.515,10.835,12.685), (11.525,12.515,11.695,12.685), (11.525,12.515,11.695,12.685), (12.385,12.515,12.555,12.685), (12.385,12.515,12.555,12.685), (13.245,12.515,13.415,12.685), (13.245,12.515,13.415,12.685), (14.105,12.515,14.275,12.685), (14.105,12.515,14.275,12.685), (14.965,12.515,15.135,12.685), (14.965,12.515,15.135,12.685), (15.825,12.515,15.995,12.685), (15.825,12.515,15.995,12.685), (16.685,12.515,16.855,12.685), (16.685,12.515,16.855,12.685), (17.545,12.515,17.715,12.685), (17.545,12.515,17.715,12.685), (18.405,12.515,18.575,12.685), (18.405,12.515,18.575,12.685), (19.265,12.515,19.435,12.685), (19.265,12.515,19.435,12.685), (20.125,12.515,20.295,12.685), (20.125,12.515,20.295,12.685), (20.985,12.515,21.155,12.685), (20.985,12.515,21.155,12.685)])
A(pmos_s_71888108_x24_y2_1, li1, 0.735, 0.335, 0.25, 3.53, 49, 2, 0.43, 5.88)
A(pmos_s_71888108_x24_y2_1, li1, 1.165, 4.115, 0.25, 1.01, 24, 2, 0.86, 5.88)
A(pmos_s_71888108_x24_y2_1, li1, 1.165, 12.095, 0.25, 1.01, 24, 1, 0.86, 0)
A(pmos_s_71888108_x24_y2_1, mcon, 1.205, 0.335, 0.17, 0.17, 24, 2, 0.86, 4.2)
A(pmos_s_71888108_x24_y2_1, mcon, 0.775, 0.755, 0.17, 0.17, 25, 2, 0.86, 5.88)
A(pmos_s_71888108_x24_y2_1, mcon, 1.205, 6.215, 0.17, 0.17, 24, 2, 0.86, 4.2)
A(pmos_s_71888108_x24_y2_1, mcon, 1.205, 12.515, 0.17, 0.17, 24, 1, 0.86, 0)
R(pmos_s_71888108_x24_y2_1, met1, [(1.12,0.28,21.24,0.56), (0.69,0.7,21.67,0.98), (1.12,4.48,21.24,4.76), (1.12,6.16,21.24,6.44), (0.69,6.58,21.67,6.86), (1.12,10.36,21.24,10.64), (1.12,12.46,21.24,12.74)])
A(pmos_s_71888108_x24_y2_1, via, 11.535, 0.765, 0.15, 0.15, 1, 3, 0, 5.88)
R(pmos_s_71888108_x24_y2_1, via, [(10.675,0.345,10.825,0.495), (11.105,4.545,11.255,4.695), (10.675,6.225,10.825,6.375), (11.105,10.425,11.255,10.575)])
R(pmos_s_71888108_x24_y2_1, met2, [(10.61,0.26,10.89,6.46), (11.47,0.68,11.75,12.76), (11.04,4.46,11.32,10.66)])
R(pmos_s_71888108_x24_y2_1, nsdm, [(0,11.76,22.36,13.44)])
R(pmos_s_71888108_x24_y2_1, psdm, [(0,0,22.36,11.76)])
R(pmos_s_71888108_x24_y2_1, L100_5, [(0,0,22.36,13.44)])

inv_80711309_0_0_1678492 = lib.new_cell('INV_80711309_0_0_1678492465')
R(inv_80711309_0_0_1678492, met1, [(11.02,2.8,11.34,3.08), (11.02,2.8,11.34,3.08), (11.45,7,11.77,7.28), (11.45,7,11.77,7.28)])
P(inv_80711309_0_0_1678492, met1, [(0,0),(0,0),(0,0),(0,0)],
  [(0,0),(0,0),(0,0),(0,0)])
R(inv_80711309_0_0_1678492, via, [(11.105,2.865,11.255,3.015), (11.105,2.865,11.255,3.015), (11.535,7.065,11.685,7.215), (11.535,7.065,11.685,7.215)])
R(inv_80711309_0_0_1678492, met2, [(11.04,2.78,11.32,3.1), (11.04,2.78,11.32,3.1), (11.04,2.94,11.32,12.18), (11.47,6.98,11.75,7.3), (11.47,6.98,11.75,7.3), (11.47,7.14,11.75,7.98)])
P(inv_80711309_0_0_1678492, met2, [(0,0),(0,0),(0,0),(0,0)],
  [(0,0),(0,0),(0,0),(0,0)],
  [(0,0),(0,0),(0,0),(0,0)],
  [(0,0),(0,0),(0,0),(0,0)])
R(inv_80711309_0_0_1678492, L235_5, [(0,0,22.36,21)])
inv_80711309_0_0_1678492.add(gdstk.Reference(nmos_s_54487678_x1_y1_16, (12.47,7.56), rotation=pi))
inv_80711309_0_0_1678492.add(gdstk.Reference(pmos_s_71888108_x24_y2_1, (22.36,7.56), rotation=pi, x_reflection=True))

lib.write_gds('INV_80711309_0_0_1678492465.gds')
